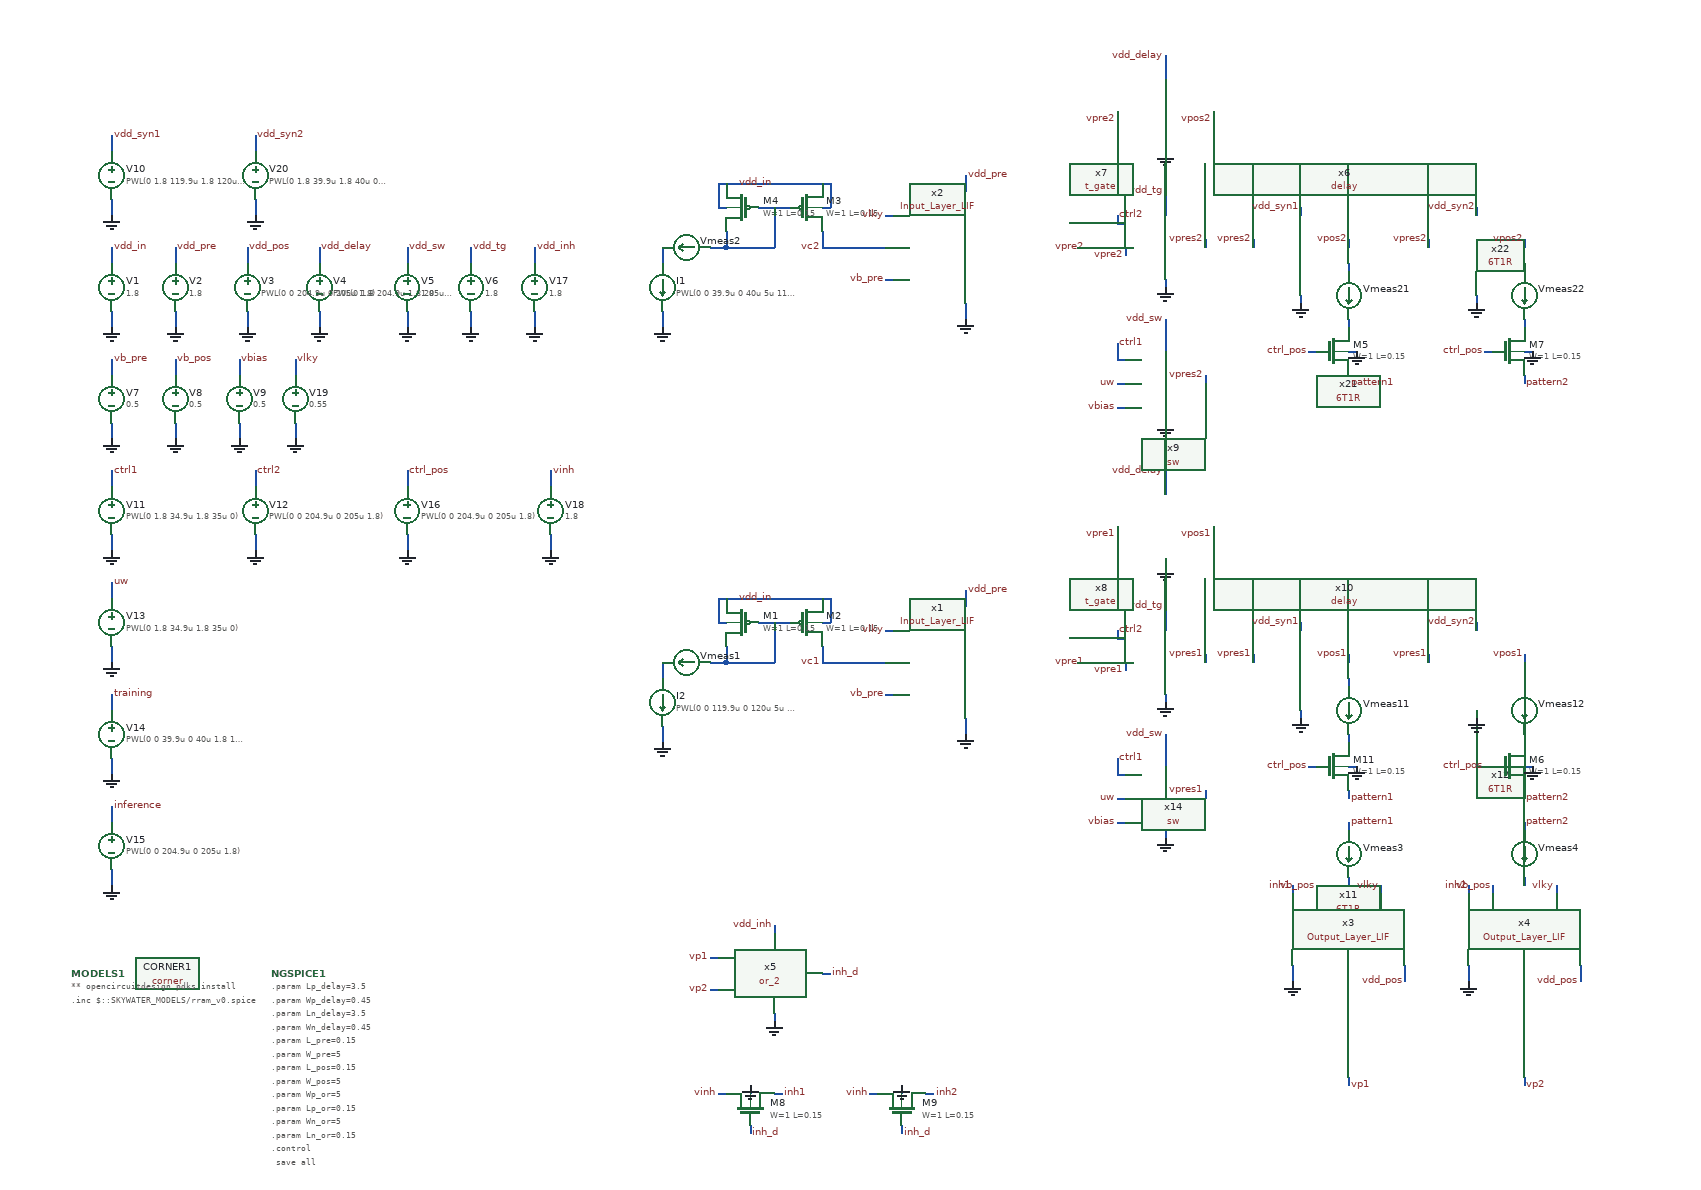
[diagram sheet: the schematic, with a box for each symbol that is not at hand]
v {xschem version=3.4.5 file_version=1.2
}
G {}
K {}
V {}
S {}
E {}
B 2 -1380 -1200 -580 -800 {flags=graph
y1=-0.12
y2=1.9
ypos1=0
ypos2=2
divy=5
subdivy=1
unity=1
x1=0.000205627
x2=0.00022002
divx=5
subdivx=1
xlabmag=1.0
ylabmag=1.0
node="\\"Vpres1 [V];vpre1\\"
\\"Vpres2 [V];vpre2\\""
color="4 6"
dataset=-1
unitx=1
logx=0
logy=0
}
B 2 -2180 -1200 -1380 -800 {flags=graph
y1=-4.4e-06
y2=7.7e-05
ypos1=0
ypos2=2
divy=5
subdivy=1
unity=1
x1=0.000205627
x2=0.00022002
divx=5
subdivx=1
xlabmag=1.0
ylabmag=1.0


dataset=-1
unitx=1
logx=0
logy=0




color="10 11 12 13"
node="\\"Isyn11 (A);i(vmeas11)\\"
\\"Isyn12 (A);i(vmeas12)\\"
\\"Isyn21 (A);i(vmeas21)\\"
\\"Isyn22 (A);i(vmeas22)\\""}
B 2 -2180 -800 -1380 -400 {flags=graph
y1=-0.008
y2=2.502
ypos1=0
ypos2=2
divy=5
subdivy=1
unity=1
x1=0.000205627
x2=0.00022002
divx=5
subdivx=1
xlabmag=1.0
ylabmag=1.0


dataset=-1
unitx=1
logx=0
logy=0


color="7 8"
node="\\"Vpos1 [V];vpos1\\"
\\"Vpos2 [V];vpos2\\""}
B 2 -1380 -800 -580 -400 {flags=graph
y1=1.4
y2=5.1
ypos1=0
ypos2=2
divy=5
subdivy=1
unity=1
x1=0.000205627
x2=0.00022002
divx=5
subdivx=1
xlabmag=1.0
ylabmag=1.0


dataset=-1
unitx=1
logx=0
logy=0




color="10 11 12 13"
node="\\"Thickness11 [nm]; 5 n.x11.xr1.n1#ngap -\\"
\\"Thickness12 [nm]; 5 n.x21.xr1.n1#ngap -\\"
\\"Thickness21 [nm]; 5 n.x12.xr1.n1#ngap -\\"
\\"Thickness22 [nm]; 5 n.x22.xr1.n1#ngap -\\""}
B 2 -1380 -400 -580 0 {flags=graph
y1=0
y2=1.8
ypos1=0
ypos2=2
divy=5
subdivy=1
unity=1
x1=0.000205627
x2=0.00022002
divx=5
subdivx=1
xlabmag=1.0
ylabmag=1.0


dataset=-1
unitx=1
logx=0
logy=0
color="7 8 11"
node="\\"Update Weights;uw\\"
\\"Training;training\\"
\\"Inference;inference\\""}
B 2 -2180 -400 -1380 0 {flags=graph
y1=0
y2=1.8
ypos1=0
ypos2=2
divy=5
subdivy=1
unity=1
x1=0.000205627
x2=0.00022002
divx=5
subdivx=1
xlabmag=1.0
ylabmag=1.0


dataset=-1
unitx=1
logx=0
logy=0


color="17 21"
node="\\"Control 1;ctrl1\\"
\\"Control 2;ctrl2\\""}
B 2 -2180 -1600 -1380 -1200 {flags=graph
y1=-1.2e-07
y2=3.6e-05
ypos1=0
ypos2=2
divy=5
subdivy=1
unity=1
x1=0.000205627
x2=0.00022002
divx=5
subdivx=1
xlabmag=1.0
ylabmag=1.0


dataset=-1
unitx=1
logx=0
logy=0






color="15 16"
node="\\"Ip1 (A);i(vmeas3)\\"
\\"Ip2 (A);i(vmeas4)\\""}
B 2 -1380 -1600 -580 -1200 {flags=graph
y1=-0.22
y2=1.9
ypos1=0
ypos2=2
divy=5
subdivy=1
unity=1
x1=0.000205627
x2=0.00022002
divx=5
subdivx=1
xlabmag=1.0
ylabmag=1.0


dataset=-1
unitx=1
logx=0
logy=0

color="15 16"
node="\\"Vp1 [V];vp1\\"
\\"Vp2 [V];vp2\\""}
B 2 -2180 -2000 -1380 -1600 {flags=graph
y1=-1.15845e-07
y2=1.4252e-06
ypos1=0
ypos2=2
divy=5
subdivy=1
unity=1
x1=0.000205627
x2=0.00022002
divx=5
subdivx=1
xlabmag=1.0
ylabmag=1.0


dataset=-1
unitx=1
logx=0
logy=0







color="10 11 12 13"
node="\\"Im11 (A);i(vmeas11)\\"
\\"Im12 (A);i(vmeas12)\\"
\\"Im21 (A);i(vmeas21)\\"
\\"Im22 (A);i(vmeas22)\\""}
B 2 -1380 -2000 -580 -1600 {flags=graph
y1=-8.9e-05
y2=0.073
ypos1=0
ypos2=2
divy=5
subdivy=1
unity=1
x1=0.000205627
x2=0.00022002
divx=5
subdivx=1
xlabmag=1.0
ylabmag=1.0


dataset=-1
unitx=1
logx=0
logy=0



color="15 16 18"
node="inh1
inh2
inh_d"}
B 2 -580 -1600 220 -1200 {flags=graph
y1=0
y2=1.8
ypos1=0
ypos2=2
divy=5
subdivy=1
unity=1
x1=0.000205627
x2=0.00022002
divx=5
subdivx=1
xlabmag=1.0
ylabmag=1.0


dataset=-1
unitx=1
logx=0
logy=0





color="15 16"
node="pattern1
pattern2"}
N -4050 -980 -4050 -960 {
lab=GND}
N -4050 -1060 -4050 -1040 {
lab=vdd_in}
N -3970 -980 -3970 -960 {
lab=GND}
N -3970 -1060 -3970 -1040 {
lab=vdd_pre}
N -2980 -470 -2980 -450 {
lab=GND}
N -2980 -630 -2980 -610 {
lab=vdd_pre}
N -3360 -460 -3360 -440 {
lab=GND}
N -3160 -560 -3160 -540 {
lab=vc1}
N -3160 -590 -3150 -590 {
lab=vdd_in}
N -3150 -620 -3150 -590 {
lab=vdd_in}
N -3160 -620 -3150 -620 {
lab=vdd_in}
N -3240 -590 -3200 -590 {
lab=#net1}
N -3280 -620 -3160 -620 {
lab=vdd_in}
N -3290 -590 -3280 -590 {
lab=vdd_in}
N -3290 -620 -3290 -590 {
lab=vdd_in}
N -3290 -620 -3280 -620 {
lab=vdd_in}
N -3280 -560 -3280 -540 {
lab=#net1}
N -3280 -540 -3220 -540 {
lab=#net1}
N -3220 -590 -3220 -540 {
lab=#net1}
N -3360 -540 -3360 -520 {
lab=#net2}
N -3790 -980 -3790 -960 {
lab=GND}
N -3790 -1060 -3790 -1040 {
lab=vdd_delay}
N -2560 -480 -2560 -470 {
lab=GND}
N -2560 -590 -2560 -580 {
lab=vdd_syn1}
N -2730 -670 -2730 -660 {
lab=GND}
N -2500 -520 -2500 -510 {
lab=#net3}
N -2500 -410 -2490 -410 {
lab=GND}
N -2500 -450 -2500 -440 {
lab=#net4}
N -2500 -380 -2500 -370 {
lab=pattern1}
N -2500 -270 -2500 -260 {
lab=#net5}
N -2500 -340 -2500 -330 {
lab=pattern1}
N -2500 -20 -2500 -10 {
lab=vp1}
N -4050 -560 -4050 -540 {
lab=GND}
N -4050 -640 -4050 -620 {
lab=uw}
N -4050 -420 -4050 -400 {
lab=GND}
N -4050 -500 -4050 -480 {
lab=training}
N -2840 -540 -2830 -540 {
lab=vpre1}
N -2570 -160 -2570 -140 {
lab=GND}
N -2430 -160 -2430 -140 {
lab=vdd_pos}
N -4050 -280 -4050 -260 {
lab=GND}
N -4050 -360 -4050 -340 {
lab=inference}
N -3300 -540 -3280 -540 {
lab=#net1}
N -4050 -700 -4050 -680 {
lab=GND}
N -4050 -780 -4050 -760 {
lab=ctrl1}
N -2730 -330 -2730 -320 {
lab=GND}
N -2680 -380 -2680 -370 {
lab=vpres1}
N -2790 -400 -2780 -400 {
lab=ctrl1}
N -2730 -500 -2730 -490 {
lab=GND}
N -2780 -540 -2780 -530 {
lab=vpre1}
N -2790 -580 -2790 -570 {
lab=ctrl2}
N -2790 -570 -2780 -570 {
lab=ctrl2}
N -3870 -700 -3870 -680 {
lab=GND}
N -3870 -780 -3870 -760 {
lab=ctrl2}
N -2790 -420 -2790 -400 {
lab=ctrl1}
N -3890 -840 -3890 -820 {
lab=GND}
N -3890 -920 -3890 -900 {
lab=vbias}
N -3880 -980 -3880 -960 {
lab=GND}
N -3880 -1060 -3880 -1040 {
lab=vdd_pos}
N -3680 -980 -3680 -960 {
lab=GND}
N -3680 -1060 -3680 -1040 {
lab=vdd_sw}
N -3600 -980 -3600 -960 {
lab=GND}
N -3600 -1060 -3600 -1040 {
lab=vdd_tg}
N -4050 -840 -4050 -820 {
lab=GND}
N -4050 -920 -4050 -900 {
lab=vb_pre}
N -3970 -840 -3970 -820 {
lab=GND}
N -3970 -920 -3970 -900 {
lab=vb_pos}
N -2730 -610 -2730 -580 {
lab=vdd_tg}
N -2730 -780 -2730 -750 {
lab=vdd_delay}
N -2730 -450 -2730 -410 {
lab=vdd_sw}
N -2790 -710 -2790 -700 {
lab=vpre1}
N -2670 -710 -2670 -700 {
lab=vpos1}
N -2680 -550 -2680 -540 {
lab=vpres1}
N -2620 -550 -2620 -540 {
lab=vpres1}
N -2500 -550 -2500 -540 {
lab=vpos1}
N -2790 -370 -2780 -370 {
lab=uw}
N -2980 -990 -2980 -970 {
lab=GND}
N -2980 -1150 -2980 -1130 {
lab=vdd_pre}
N -3360 -980 -3360 -960 {
lab=GND}
N -3160 -1080 -3160 -1060 {
lab=vc2}
N -3160 -1110 -3150 -1110 {
lab=vdd_in}
N -3150 -1140 -3150 -1110 {
lab=vdd_in}
N -3160 -1140 -3150 -1140 {
lab=vdd_in}
N -3240 -1110 -3200 -1110 {
lab=#net6}
N -3280 -1140 -3160 -1140 {
lab=vdd_in}
N -3290 -1110 -3280 -1110 {
lab=vdd_in}
N -3290 -1140 -3290 -1110 {
lab=vdd_in}
N -3290 -1140 -3280 -1140 {
lab=vdd_in}
N -3280 -1080 -3280 -1060 {
lab=#net6}
N -3280 -1060 -3220 -1060 {
lab=#net6}
N -3220 -1110 -3220 -1060 {
lab=#net6}
N -3360 -1060 -3360 -1040 {
lab=#net7}
N -2560 -1000 -2560 -990 {
lab=GND}
N -2560 -1110 -2560 -1100 {
lab=vdd_syn1}
N -2730 -1190 -2730 -1180 {
lab=GND}
N -2500 -1040 -2500 -1030 {
lab=#net8}
N -2500 -930 -2490 -930 {
lab=GND}
N -2500 -970 -2500 -960 {
lab=#net9}
N -2500 -900 -2500 -890 {
lab=pattern1}
N -2840 -1060 -2830 -1060 {
lab=vpre2}
N -3300 -1060 -3280 -1060 {
lab=#net6}
N -2730 -850 -2730 -840 {
lab=GND}
N -2680 -900 -2680 -890 {
lab=vpres2}
N -2790 -920 -2780 -920 {
lab=ctrl1}
N -2730 -1020 -2730 -1010 {
lab=GND}
N -2780 -1060 -2780 -1050 {
lab=vpre2}
N -2790 -1100 -2790 -1090 {
lab=ctrl2}
N -2790 -1090 -2780 -1090 {
lab=ctrl2}
N -2790 -940 -2790 -920 {
lab=ctrl1}
N -2730 -1130 -2730 -1100 {
lab=vdd_tg}
N -2730 -1300 -2730 -1270 {
lab=vdd_delay}
N -2730 -970 -2730 -930 {
lab=vdd_sw}
N -2790 -1230 -2790 -1220 {
lab=vpre2}
N -2670 -1230 -2670 -1220 {
lab=vpos2}
N -2680 -1070 -2680 -1060 {
lab=vpres2}
N -2620 -1070 -2620 -1060 {
lab=vpres2}
N -2500 -1070 -2500 -1060 {
lab=vpos2}
N -2790 -890 -2780 -890 {
lab=uw}
N -2340 -480 -2340 -470 {
lab=GND}
N -2340 -590 -2340 -580 {
lab=vdd_syn2}
N -2280 -520 -2280 -510 {
lab=#net10}
N -2280 -410 -2270 -410 {
lab=GND}
N -2280 -450 -2280 -440 {
lab=#net11}
N -2280 -380 -2280 -370 {
lab=pattern2}
N -2400 -550 -2400 -540 {
lab=vpres1}
N -2280 -550 -2280 -540 {
lab=vpos1}
N -2340 -1000 -2340 -990 {
lab=GND}
N -2340 -1110 -2340 -1100 {
lab=vdd_syn2}
N -2280 -1040 -2280 -1030 {
lab=#net12}
N -2280 -930 -2270 -930 {
lab=GND}
N -2280 -970 -2280 -960 {
lab=#net13}
N -2280 -900 -2280 -890 {
lab=pattern2}
N -2400 -1070 -2400 -1060 {
lab=vpres2}
N -2280 -1070 -2280 -1060 {
lab=vpos2}
N -2550 -930 -2540 -930 {
lab=ctrl_pos}
N -2330 -930 -2320 -930 {
lab=ctrl_pos}
N -2550 -410 -2540 -410 {
lab=ctrl_pos}
N -2330 -410 -2320 -410 {
lab=ctrl_pos}
N -3680 -700 -3680 -680 {
lab=GND}
N -3680 -780 -3680 -760 {
lab=ctrl_pos}
N -3520 -980 -3520 -960 {
lab=GND}
N -3520 -1060 -3520 -1040 {
lab=vdd_inh}
N -3220 -210 -3220 -200 {
lab=vdd_inh}
N -3300 -170 -3290 -170 {
lab=vp1}
N -3300 -130 -3290 -130 {
lab=vp2}
N -3500 -700 -3500 -680 {
lab=GND}
N -3500 -780 -3500 -760 {
lab=vinh}
N -3220 -100 -3220 -90 {
lab=GND}
N -3160 -150 -3150 -150 {
lab=inh_d}
N -3220 0 -3210 0 {
lab=inh1}
N -3250 -10 -3250 0 {
lab=GND}
N -3250 40 -3250 50 {
lab=inh_d}
N -3290 0 -3280 0 {
lab=vinh}
N -3030 0 -3020 0 {
lab=inh2}
N -3060 -10 -3060 0 {
lab=GND}
N -3060 40 -3060 50 {
lab=inh_d}
N -3100 0 -3090 0 {
lab=vinh}
N -3820 -840 -3820 -820 {
lab=GND}
N -3820 -920 -3820 -900 {
lab=vlky}
N -3160 -1060 -3080 -1060 {
lab=vc2}
N -3080 -1100 -3070 -1100 {
lab=vlky}
N -3080 -1020 -3070 -1020 {
lab=vb_pre}
N -3080 -580 -3070 -580 {
lab=vlky}
N -3160 -540 -3080 -540 {
lab=vc1}
N -3080 -500 -3070 -500 {
lab=vb_pre}
N -2570 -260 -2570 -250 {
lab=inh1}
N -2540 -260 -2540 -250 {
lab=vb_pos}
N -2460 -260 -2460 -250 {
lab=vlky}
N -2280 -270 -2280 -260 {
lab=#net14}
N -2280 -340 -2280 -330 {
lab=pattern2}
N -2280 -20 -2280 -10 {
lab=vp2}
N -2350 -160 -2350 -140 {
lab=GND}
N -2210 -160 -2210 -140 {
lab=vdd_pos}
N -2350 -260 -2350 -250 {
lab=inh2}
N -2320 -260 -2320 -250 {
lab=vb_pos}
N -2240 -260 -2240 -250 {
lab=vlky}
N -4050 -1120 -4050 -1100 {
lab=GND}
N -4050 -1200 -4050 -1180 {
lab=vdd_syn1}
N -3870 -1120 -3870 -1100 {
lab=GND}
N -3870 -1200 -3870 -1180 {
lab=vdd_syn2}
N -2790 -860 -2780 -860 {
lab=vbias}
N -2790 -340 -2780 -340 {
lab=vbias}
C {devices/vsource.sym} -4050 -1010 0 0 {name=V1 value=1.8}
C {devices/gnd.sym} -4050 -960 0 0 {name=l6 lab=GND}
C {devices/vsource.sym} -3970 -1010 0 0 {name=V2 value=1.8}
C {devices/gnd.sym} -3970 -960 0 0 {name=l9 lab=GND}
C {devices/lab_pin.sym} -3970 -1060 2 0 {name=p9 sig_type=std_logic lab=vdd_pre}
C {devices/gnd.sym} -2980 -450 0 0 {name=l13 lab=GND}
C {devices/lab_pin.sym} -3080 -500 0 0 {name=p13 sig_type=std_logic lab=vb_pre}
C {devices/isource.sym} -3360 -490 0 0 {name=I2 value="PWL(0 0 119.9u 0 120u 5u 199.9u 5u 200u 0 204.9u 0 205u 5u 209.9u 5u 210u 0 214.9u 0 215u 5u)"}
C {devices/gnd.sym} -3360 -440 0 0 {name=l20 lab=GND}
C {sky130_fd_pr/pfet_01v8.sym} -3180 -590 0 0 {name=M2
L=0.15
W=1
nf=1
mult=1
ad="'int((nf+1)/2) * W/nf * 0.29'" 
pd="'2*int((nf+1)/2) * (W/nf + 0.29)'"
as="'int((nf+2)/2) * W/nf * 0.29'" 
ps="'2*int((nf+2)/2) * (W/nf + 0.29)'"
nrd="'0.29 / W'" nrs="'0.29 / W'"
sa=0 sb=0 sd=0
model=pfet_01v8
spiceprefix=X
}
C {sky130_fd_pr/pfet_01v8.sym} -3260 -590 0 1 {name=M1
L=0.15
W=1
nf=1
mult=1
ad="'int((nf+1)/2) * W/nf * 0.29'" 
pd="'2*int((nf+1)/2) * (W/nf + 0.29)'"
as="'int((nf+2)/2) * W/nf * 0.29'" 
ps="'2*int((nf+2)/2) * (W/nf + 0.29)'"
nrd="'0.29 / W'" nrs="'0.29 / W'"
sa=0 sb=0 sd=0
model=pfet_01v8
spiceprefix=X
}
C {sky130_fd_pr/corner.sym} -3980 -150 0 0 {name=CORNER1 only_toplevel=true corner=tt}
C {devices/code.sym} -4100 -150 0 0 {name=MODELS1
only_toplevel=true
format="tcleval( @value )"
value="
** opencircuitdesign pdks install
.inc $::SKYWATER_MODELS/rram_v0.spice
"
spice_ignore=false}
C {devices/code_shown.sym} -3850 -150 0 0 {name=NGSPICE1
only_toplevel=true
value="
.param Lp_delay=3.5
.param Wp_delay=0.45
.param Ln_delay=3.5
.param Wn_delay=0.45
.param L_pre=0.15
.param W_pre=5
.param L_pos=0.15
.param W_pos=5
.param Wp_or=5
.param Lp_or=0.15
.param Wn_or=5
.param Ln_or=0.15
.control
  save all
  tran 10n 220u
  write SNN_2x2_tb.raw
.endc
" }
C {devices/launcher.sym} -2330 -1230 0 0 {name=h1
descr="load waves" 
tclcommand="xschem raw_read $netlist_dir/SNN_2x2_tb.raw tran"
}
C {devices/lab_pin.sym} -3160 -540 0 0 {name=p10 sig_type=std_logic lab=vc1}
C {devices/vsource.sym} -3790 -1010 0 0 {name=V4 value="PWL(0 1.8 204.9u 1.8 205u 0)"}
C {devices/gnd.sym} -3790 -960 0 0 {name=l29 lab=GND}
C {devices/lab_pin.sym} -3790 -1060 2 0 {name=p16 sig_type=std_logic lab=vdd_delay}
C {/home/ricardo/RATT_repos/Proyectos_xschem/synapse/6T1R.sym} -2500 -360 0 0 {name=x11}
C {devices/gnd.sym} -2560 -470 0 0 {name=l39 lab=GND}
C {/home/ricardo/RATT_repos/Proyectos_xschem/delay/delay.sym} -2550 -590 0 0 {name=x10}
C {devices/lab_pin.sym} -2620 -550 1 0 {name=p26 sig_type=std_logic lab=vpres1}
C {devices/lab_pin.sym} -2500 -550 1 0 {name=p27 sig_type=std_logic lab=vpos1}
C {devices/gnd.sym} -2730 -660 0 0 {name=l40 lab=GND}
C {devices/lab_pin.sym} -2670 -700 3 0 {name=p28 sig_type=std_logic lab=vpos1}
C {devices/lab_pin.sym} -2790 -700 3 0 {name=p33 sig_type=std_logic lab=vpre1}
C {devices/ammeter.sym} -2500 -480 0 0 {name=Vmeas11 savecurrent=true}
C {sky130_fd_pr/nfet_01v8.sym} -2520 -410 0 0 {name=M11
L=0.15
W=1
nf=1 
mult=1
ad="'int((nf+1)/2) * W/nf * 0.29'" 
pd="'2*int((nf+1)/2) * (W/nf + 0.29)'"
as="'int((nf+2)/2) * W/nf * 0.29'" 
ps="'2*int((nf+2)/2) * (W/nf + 0.29)'"
nrd="'0.29 / W'" nrs="'0.29 / W'"
sa=0 sb=0 sd=0
model=nfet_01v8
spiceprefix=X
}
C {devices/gnd.sym} -2490 -410 3 0 {name=l4 lab=GND}
C {devices/lab_pin.sym} -2500 -370 2 0 {name=p46 sig_type=std_logic lab=pattern1}
C {devices/lab_pin.sym} -2680 -380 1 0 {name=p24 sig_type=std_logic lab=vpres1}
C {devices/lab_pin.sym} -2790 -370 0 0 {name=p53 sig_type=std_logic lab=uw}
C {devices/lab_pin.sym} -2540 -260 1 0 {name=p59 sig_type=std_logic lab=vb_pos}
C {devices/gnd.sym} -2570 -140 0 0 {name=l63 lab=GND}
C {devices/ammeter.sym} -2500 -300 0 0 {name=Vmeas3 savecurrent=true}
C {devices/lab_pin.sym} -2500 -340 2 0 {name=p60 sig_type=std_logic lab=pattern1}
C {devices/lab_pin.sym} -2500 -10 2 0 {name=p61 sig_type=std_logic lab=vp1}
C {devices/vsource.sym} -4050 -590 0 0 {name=V13 value="PWL(0 1.8 34.9u 1.8 35u 0)"}
C {devices/gnd.sym} -4050 -540 0 0 {name=l67 lab=GND}
C {devices/lab_pin.sym} -4050 -640 2 0 {name=p65 sig_type=std_logic lab=uw}
C {devices/vsource.sym} -4050 -450 0 0 {name=V14 value="PWL(0 0 39.9u 0 40u 1.8 199.9u 1.8 200u 0)"}
C {devices/gnd.sym} -4050 -400 0 0 {name=l68 lab=GND}
C {devices/lab_pin.sym} -4050 -500 2 0 {name=p66 sig_type=std_logic lab=training}
C {devices/lab_pin.sym} -2830 -540 1 0 {name=p69 sig_type=std_logic lab=vpre1}
C {devices/vsource.sym} -4050 -310 0 0 {name=V15 value="PWL(0 0 204.9u 0 205u 1.8)"}
C {devices/gnd.sym} -4050 -260 0 0 {name=l69 lab=GND}
C {devices/lab_pin.sym} -4050 -360 2 0 {name=p73 sig_type=std_logic lab=inference}
C {devices/ammeter.sym} -3330 -540 1 0 {name=Vmeas1 savecurrent=true}
C {devices/lab_pin.sym} -2790 -420 2 0 {name=p74 sig_type=std_logic lab=ctrl1}
C {devices/vsource.sym} -4050 -730 0 0 {name=V11 value="PWL(0 1.8 34.9u 1.8 35u 0)"}
C {devices/gnd.sym} -4050 -680 0 0 {name=l72 lab=GND}
C {devices/lab_pin.sym} -4050 -780 2 0 {name=p75 sig_type=std_logic lab=ctrl1}
C {devices/gnd.sym} -2730 -320 0 0 {name=l32 lab=GND}
C {devices/lab_pin.sym} -2680 -550 1 0 {name=p2 sig_type=std_logic lab=vpres1}
C {devices/lab_pin.sym} -2780 -530 3 0 {name=p5 sig_type=std_logic lab=vpre1}
C {devices/lab_pin.sym} -2790 -580 2 0 {name=p14 sig_type=std_logic lab=ctrl2}
C {devices/gnd.sym} -2730 -490 0 0 {name=l33 lab=GND}
C {devices/vsource.sym} -3870 -730 0 0 {name=V12 value="PWL(0 0 204.9u 0 205u 1.8)"}
C {devices/gnd.sym} -3870 -680 0 0 {name=l35 lab=GND}
C {devices/lab_pin.sym} -3870 -780 2 0 {name=p17 sig_type=std_logic lab=ctrl2}
C {devices/vsource.sym} -3890 -870 0 0 {name=V9 value=0.5}
C {devices/gnd.sym} -3890 -820 0 0 {name=l75 lab=GND}
C {devices/lab_pin.sym} -3890 -920 2 0 {name=p82 sig_type=std_logic lab=vbias}
C {devices/vsource.sym} -3880 -1010 0 0 {name=V3 value="PWL(0 0 204.9u 0 205u 1.8)"}
C {devices/gnd.sym} -3880 -960 0 0 {name=l5 lab=GND}
C {devices/lab_pin.sym} -3880 -1060 2 0 {name=p6 sig_type=std_logic lab=vdd_pos}
C {devices/vsource.sym} -3680 -1010 0 0 {name=V5 value=1.8}
C {devices/gnd.sym} -3680 -960 0 0 {name=l1 lab=GND}
C {devices/lab_pin.sym} -3680 -1060 2 0 {name=p1 sig_type=std_logic lab=vdd_sw}
C {devices/vsource.sym} -3600 -1010 0 0 {name=V6 value=1.8}
C {devices/gnd.sym} -3600 -960 0 0 {name=l2 lab=GND}
C {devices/lab_pin.sym} -3600 -1060 2 0 {name=p3 sig_type=std_logic lab=vdd_tg}
C {devices/vsource.sym} -4050 -870 0 0 {name=V7 value=0.5}
C {devices/gnd.sym} -4050 -820 0 0 {name=l10 lab=GND}
C {devices/lab_pin.sym} -4050 -920 2 0 {name=p8 sig_type=std_logic lab=vb_pre}
C {devices/vsource.sym} -3970 -870 0 0 {name=V8 value=0.5}
C {devices/gnd.sym} -3970 -820 0 0 {name=l11 lab=GND}
C {devices/lab_pin.sym} -3970 -920 2 0 {name=p11 sig_type=std_logic lab=vb_pos}
C {devices/lab_pin.sym} -2980 -630 2 0 {name=p4 sig_type=std_logic lab=vdd_pre}
C {devices/lab_pin.sym} -2430 -140 3 0 {name=p12 sig_type=std_logic lab=vdd_pos}
C {devices/lab_pin.sym} -2560 -590 1 0 {name=p15 sig_type=std_logic lab=vdd_syn1}
C {devices/lab_pin.sym} -2730 -780 0 0 {name=p18 sig_type=std_logic lab=vdd_delay}
C {devices/lab_pin.sym} -2730 -450 0 0 {name=p19 sig_type=std_logic lab=vdd_sw}
C {devices/lab_pin.sym} -2730 -610 0 0 {name=p20 sig_type=std_logic lab=vdd_tg}
C {devices/lab_pin.sym} -4050 -1060 2 0 {name=p21 sig_type=std_logic lab=vdd_in}
C {devices/lab_pin.sym} -3220 -620 1 0 {name=p40 sig_type=std_logic lab=vdd_in}
C {devices/gnd.sym} -2980 -970 0 0 {name=l12 lab=GND}
C {devices/lab_pin.sym} -3080 -1020 0 0 {name=p23 sig_type=std_logic lab=vb_pre}
C {devices/isource.sym} -3360 -1010 0 0 {name=I1 value="PWL(0 0 39.9u 0 40u 5u 119.9u 5u 120u 0 209.9u 0 210u 5u 214.9u 5u 215u 0)"}
C {devices/gnd.sym} -3360 -960 0 0 {name=l14 lab=GND}
C {sky130_fd_pr/pfet_01v8.sym} -3180 -1110 0 0 {name=M3
L=0.15
W=1
nf=1
mult=1
ad="'int((nf+1)/2) * W/nf * 0.29'" 
pd="'2*int((nf+1)/2) * (W/nf + 0.29)'"
as="'int((nf+2)/2) * W/nf * 0.29'" 
ps="'2*int((nf+2)/2) * (W/nf + 0.29)'"
nrd="'0.29 / W'" nrs="'0.29 / W'"
sa=0 sb=0 sd=0
model=pfet_01v8
spiceprefix=X
}
C {sky130_fd_pr/pfet_01v8.sym} -3260 -1110 0 1 {name=M4
L=0.15
W=1
nf=1
mult=1
ad="'int((nf+1)/2) * W/nf * 0.29'" 
pd="'2*int((nf+1)/2) * (W/nf + 0.29)'"
as="'int((nf+2)/2) * W/nf * 0.29'" 
ps="'2*int((nf+2)/2) * (W/nf + 0.29)'"
nrd="'0.29 / W'" nrs="'0.29 / W'"
sa=0 sb=0 sd=0
model=pfet_01v8
spiceprefix=X
}
C {devices/lab_pin.sym} -3160 -1060 0 0 {name=p25 sig_type=std_logic lab=vc2}
C {/home/ricardo/RATT_repos/Proyectos_xschem/synapse/6T1R.sym} -2500 -880 0 0 {name=x21}
C {devices/gnd.sym} -2560 -990 0 0 {name=l15 lab=GND}
C {/home/ricardo/RATT_repos/Proyectos_xschem/delay/delay.sym} -2550 -1110 0 0 {name=x6}
C {devices/lab_pin.sym} -2620 -1070 1 0 {name=p29 sig_type=std_logic lab=vpres2}
C {devices/lab_pin.sym} -2500 -1070 1 0 {name=p30 sig_type=std_logic lab=vpos2}
C {devices/gnd.sym} -2730 -1180 0 0 {name=l16 lab=GND}
C {devices/lab_pin.sym} -2670 -1220 3 0 {name=p31 sig_type=std_logic lab=vpos2}
C {devices/lab_pin.sym} -2790 -1220 3 0 {name=p32 sig_type=std_logic lab=vpre2}
C {devices/ammeter.sym} -2500 -1000 0 0 {name=Vmeas21 savecurrent=true}
C {sky130_fd_pr/nfet_01v8.sym} -2520 -930 0 0 {name=M5
L=0.15
W=1
nf=1 
mult=1
ad="'int((nf+1)/2) * W/nf * 0.29'" 
pd="'2*int((nf+1)/2) * (W/nf + 0.29)'"
as="'int((nf+2)/2) * W/nf * 0.29'" 
ps="'2*int((nf+2)/2) * (W/nf + 0.29)'"
nrd="'0.29 / W'" nrs="'0.29 / W'"
sa=0 sb=0 sd=0
model=nfet_01v8
spiceprefix=X
}
C {devices/gnd.sym} -2490 -930 3 0 {name=l17 lab=GND}
C {devices/lab_pin.sym} -2500 -890 2 0 {name=p34 sig_type=std_logic lab=pattern1}
C {devices/lab_pin.sym} -2680 -900 1 0 {name=p35 sig_type=std_logic lab=vpres2}
C {devices/lab_pin.sym} -2790 -890 0 0 {name=p36 sig_type=std_logic lab=uw}
C {devices/lab_pin.sym} -2830 -1060 1 0 {name=p37 sig_type=std_logic lab=vpre2}
C {devices/ammeter.sym} -3330 -1060 1 0 {name=Vmeas2 savecurrent=true}
C {devices/lab_pin.sym} -2790 -940 2 0 {name=p38 sig_type=std_logic lab=ctrl1}
C {devices/gnd.sym} -2730 -840 0 0 {name=l18 lab=GND}
C {devices/lab_pin.sym} -2680 -1070 1 0 {name=p39 sig_type=std_logic lab=vpres2}
C {devices/lab_pin.sym} -2780 -1050 3 0 {name=p41 sig_type=std_logic lab=vpre2}
C {devices/lab_pin.sym} -2790 -1100 2 0 {name=p42 sig_type=std_logic lab=ctrl2}
C {devices/gnd.sym} -2730 -1010 0 0 {name=l19 lab=GND}
C {devices/lab_pin.sym} -2980 -1150 2 0 {name=p43 sig_type=std_logic lab=vdd_pre}
C {devices/lab_pin.sym} -2560 -1110 1 0 {name=p44 sig_type=std_logic lab=vdd_syn1}
C {devices/lab_pin.sym} -2730 -1300 0 0 {name=p45 sig_type=std_logic lab=vdd_delay}
C {devices/lab_pin.sym} -2730 -970 0 0 {name=p47 sig_type=std_logic lab=vdd_sw}
C {devices/lab_pin.sym} -2730 -1130 0 0 {name=p48 sig_type=std_logic lab=vdd_tg}
C {devices/lab_pin.sym} -3220 -1140 1 0 {name=p50 sig_type=std_logic lab=vdd_in}
C {/home/ricardo/RATT_repos/Proyectos_xschem/synapse/6T1R.sym} -2280 -360 0 0 {name=x12}
C {devices/gnd.sym} -2340 -470 0 0 {name=l8 lab=GND}
C {devices/lab_pin.sym} -2400 -550 1 0 {name=p52 sig_type=std_logic lab=vpres1}
C {devices/lab_pin.sym} -2280 -550 1 0 {name=p54 sig_type=std_logic lab=vpos1}
C {devices/ammeter.sym} -2280 -480 0 0 {name=Vmeas12 savecurrent=true}
C {sky130_fd_pr/nfet_01v8.sym} -2300 -410 0 0 {name=M6
L=0.15
W=1
nf=1 
mult=1
ad="'int((nf+1)/2) * W/nf * 0.29'" 
pd="'2*int((nf+1)/2) * (W/nf + 0.29)'"
as="'int((nf+2)/2) * W/nf * 0.29'" 
ps="'2*int((nf+2)/2) * (W/nf + 0.29)'"
nrd="'0.29 / W'" nrs="'0.29 / W'"
sa=0 sb=0 sd=0
model=nfet_01v8
spiceprefix=X
}
C {devices/gnd.sym} -2270 -410 3 0 {name=l21 lab=GND}
C {devices/lab_pin.sym} -2280 -370 2 0 {name=p55 sig_type=std_logic lab=pattern2}
C {devices/lab_pin.sym} -2340 -590 1 0 {name=p63 sig_type=std_logic lab=vdd_syn2}
C {/home/ricardo/RATT_repos/Proyectos_xschem/synapse/6T1R.sym} -2280 -880 0 0 {name=x22}
C {devices/gnd.sym} -2340 -990 0 0 {name=l23 lab=GND}
C {devices/lab_pin.sym} -2400 -1070 1 0 {name=p64 sig_type=std_logic lab=vpres2}
C {devices/lab_pin.sym} -2280 -1070 1 0 {name=p67 sig_type=std_logic lab=vpos2}
C {devices/ammeter.sym} -2280 -1000 0 0 {name=Vmeas22 savecurrent=true}
C {sky130_fd_pr/nfet_01v8.sym} -2300 -930 0 0 {name=M7
L=0.15
W=1
nf=1 
mult=1
ad="'int((nf+1)/2) * W/nf * 0.29'" 
pd="'2*int((nf+1)/2) * (W/nf + 0.29)'"
as="'int((nf+2)/2) * W/nf * 0.29'" 
ps="'2*int((nf+2)/2) * (W/nf + 0.29)'"
nrd="'0.29 / W'" nrs="'0.29 / W'"
sa=0 sb=0 sd=0
model=nfet_01v8
spiceprefix=X
}
C {devices/gnd.sym} -2270 -930 3 0 {name=l24 lab=GND}
C {devices/lab_pin.sym} -2280 -890 2 0 {name=p68 sig_type=std_logic lab=pattern2}
C {devices/lab_pin.sym} -2340 -1110 1 0 {name=p70 sig_type=std_logic lab=vdd_syn2}
C {devices/lab_pin.sym} -2550 -930 0 0 {name=p76 sig_type=std_logic lab=ctrl_pos}
C {devices/lab_pin.sym} -2330 -930 0 0 {name=p77 sig_type=std_logic lab=ctrl_pos}
C {devices/lab_pin.sym} -2550 -410 0 0 {name=p78 sig_type=std_logic lab=ctrl_pos}
C {devices/lab_pin.sym} -2330 -410 0 0 {name=p79 sig_type=std_logic lab=ctrl_pos}
C {devices/vsource.sym} -3680 -730 0 0 {name=V16 value="PWL(0 0 204.9u 0 205u 1.8)"}
C {devices/gnd.sym} -3680 -680 0 0 {name=l25 lab=GND}
C {devices/lab_pin.sym} -3680 -780 2 0 {name=p71 sig_type=std_logic lab=ctrl_pos}
C {devices/vsource.sym} -3520 -1010 0 0 {name=V17 value=1.8}
C {devices/gnd.sym} -3520 -960 0 0 {name=l26 lab=GND}
C {devices/lab_pin.sym} -3520 -1060 2 0 {name=p80 sig_type=std_logic lab=vdd_inh}
C {/home/ricardo/RATT_repos/Proyectos_xschem/inhibitory/or_2.sym} -3220 -150 0 0 {name=x5}
C {devices/gnd.sym} -3220 -90 0 0 {name=l27 lab=GND}
C {devices/lab_pin.sym} -3220 -210 0 0 {name=p81 sig_type=std_logic lab=vdd_inh}
C {devices/lab_pin.sym} -3300 -170 0 0 {name=p83 sig_type=std_logic lab=vp1}
C {devices/lab_pin.sym} -3300 -130 0 0 {name=p84 sig_type=std_logic lab=vp2}
C {devices/lab_pin.sym} -2570 -260 1 0 {name=p87 sig_type=std_logic lab=inh1}
C {devices/vsource.sym} -3500 -730 0 0 {name=V18 value=1.8}
C {devices/gnd.sym} -3500 -680 0 0 {name=l28 lab=GND}
C {devices/lab_pin.sym} -3500 -780 2 0 {name=p88 sig_type=std_logic lab=vinh}
C {devices/lab_pin.sym} -3150 -150 2 0 {name=p91 sig_type=std_logic lab=inh_d}
C {devices/lab_pin.sym} -3210 0 2 0 {name=p94 sig_type=std_logic lab=inh1}
C {sky130_fd_pr/nfet_01v8.sym} -3250 20 3 0 {name=M8
L=0.15
W=1
nf=1 
mult=1
ad="'int((nf+1)/2) * W/nf * 0.29'" 
pd="'2*int((nf+1)/2) * (W/nf + 0.29)'"
as="'int((nf+2)/2) * W/nf * 0.29'" 
ps="'2*int((nf+2)/2) * (W/nf + 0.29)'"
nrd="'0.29 / W'" nrs="'0.29 / W'"
sa=0 sb=0 sd=0
model=nfet_01v8
spiceprefix=X
}
C {devices/gnd.sym} -3250 -10 2 0 {name=l31 lab=GND}
C {devices/lab_pin.sym} -3250 50 2 0 {name=p72 sig_type=std_logic lab=inh_d}
C {devices/lab_pin.sym} -3290 0 0 0 {name=p85 sig_type=std_logic lab=vinh}
C {devices/lab_pin.sym} -3020 0 2 0 {name=p89 sig_type=std_logic lab=inh2}
C {sky130_fd_pr/nfet_01v8.sym} -3060 20 3 0 {name=M9
L=0.15
W=1
nf=1 
mult=1
ad="'int((nf+1)/2) * W/nf * 0.29'" 
pd="'2*int((nf+1)/2) * (W/nf + 0.29)'"
as="'int((nf+2)/2) * W/nf * 0.29'" 
ps="'2*int((nf+2)/2) * (W/nf + 0.29)'"
nrd="'0.29 / W'" nrs="'0.29 / W'"
sa=0 sb=0 sd=0
model=nfet_01v8
spiceprefix=X
}
C {devices/gnd.sym} -3060 -10 2 0 {name=l34 lab=GND}
C {devices/lab_pin.sym} -3060 50 2 0 {name=p90 sig_type=std_logic lab=inh_d}
C {devices/lab_pin.sym} -3100 0 0 0 {name=p93 sig_type=std_logic lab=vinh}
C {/home/ricardo/RATT_repos/Proyectos_xschem/LIF_neuron/Input_Layer_LIF.sym} -2980 -540 0 0 {name=x1}
C {/home/ricardo/RATT_repos/Proyectos_xschem/LIF_neuron/Input_Layer_LIF.sym} -2980 -1060 0 0 {name=x2}
C {/home/ricardo/RATT_repos/Proyectos_xschem/LIF_neuron/Output_Layer_LIF.sym} -2500 -160 1 0 {name=x3}
C {devices/vsource.sym} -3820 -870 0 0 {name=V19 value=0.55}
C {devices/gnd.sym} -3820 -820 0 0 {name=l36 lab=GND}
C {devices/lab_pin.sym} -3820 -920 2 0 {name=p95 sig_type=std_logic lab=vlky}
C {devices/lab_pin.sym} -3080 -1100 1 0 {name=p96 sig_type=std_logic lab=vlky}
C {devices/lab_pin.sym} -3080 -580 1 0 {name=p97 sig_type=std_logic lab=vlky}
C {devices/lab_pin.sym} -2460 -260 1 0 {name=p56 sig_type=std_logic lab=vlky}
C {devices/lab_pin.sym} -2320 -260 1 0 {name=p57 sig_type=std_logic lab=vb_pos}
C {devices/gnd.sym} -2350 -140 0 0 {name=l22 lab=GND}
C {devices/ammeter.sym} -2280 -300 0 0 {name=Vmeas4 savecurrent=true}
C {devices/lab_pin.sym} -2280 -340 2 0 {name=p58 sig_type=std_logic lab=pattern2}
C {devices/lab_pin.sym} -2280 -10 2 0 {name=p62 sig_type=std_logic lab=vp2}
C {devices/lab_pin.sym} -2210 -140 3 0 {name=p86 sig_type=std_logic lab=vdd_pos}
C {devices/lab_pin.sym} -2350 -260 1 0 {name=p98 sig_type=std_logic lab=inh2}
C {/home/ricardo/RATT_repos/Proyectos_xschem/LIF_neuron/Output_Layer_LIF.sym} -2280 -160 1 0 {name=x4}
C {devices/lab_pin.sym} -2240 -260 1 0 {name=p99 sig_type=std_logic lab=vlky}
C {devices/vsource.sym} -4050 -1150 0 0 {name=V10 value="PWL(0 1.8 119.9u 1.8 120u 0 204.9u 0 205u 1.8)"}
C {devices/gnd.sym} -4050 -1100 0 0 {name=l3 lab=GND}
C {devices/lab_pin.sym} -4050 -1200 2 0 {name=p7 sig_type=std_logic lab=vdd_syn1}
C {devices/vsource.sym} -3870 -1150 0 0 {name=V20 value="PWL(0 1.8 39.9u 1.8 40u 0 119.9u 0 120u 1.8 199.9u 1.8 200u 0 204.9u 0 205u 1.8)"}
C {devices/gnd.sym} -3870 -1100 0 0 {name=l7 lab=GND}
C {devices/lab_pin.sym} -3870 -1200 2 0 {name=p51 sig_type=std_logic lab=vdd_syn2}
C {/home/ricardo/RATT_repos/Proyectos_xschem/switch/sw.sym} -2730 -890 0 0 {name=x9}
C {devices/lab_pin.sym} -2790 -340 0 0 {name=p49 sig_type=std_logic lab=vbias}
C {/home/ricardo/RATT_repos/Proyectos_xschem/switch/sw.sym} -2730 -370 0 0 {name=x14}
C {devices/lab_pin.sym} -2790 -860 0 0 {name=p100 sig_type=std_logic lab=vbias}
C {/home/ricardo/RATT_repos/Proyectos_xschem/switch/t_gate.sym} -2730 -1060 0 0 {name=x7}
C {/home/ricardo/RATT_repos/Proyectos_xschem/switch/t_gate.sym} -2730 -540 0 0 {name=x8}
